One B-rep face of a CAD part: STEP entity #48906.
In plain terms, the planar face has unit normal (0, 0, 1).
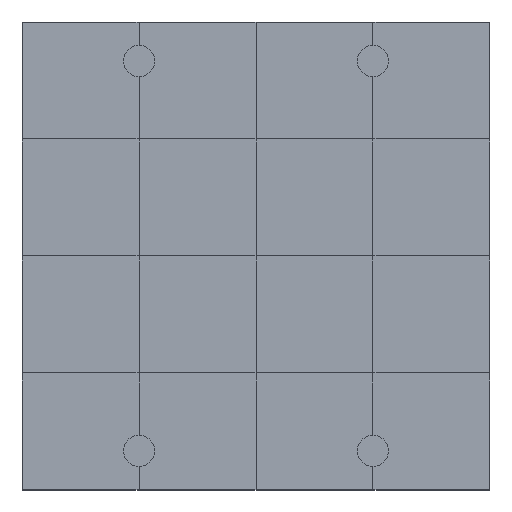
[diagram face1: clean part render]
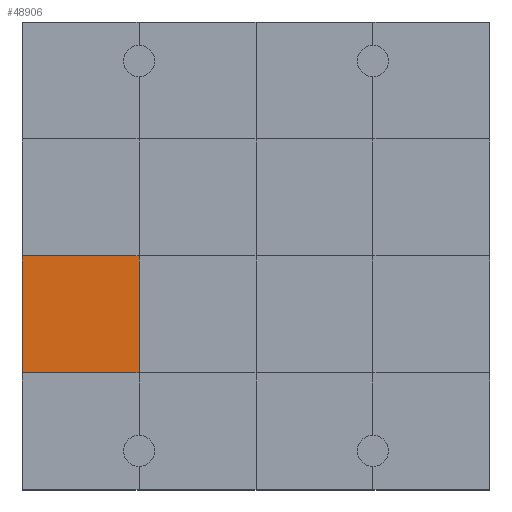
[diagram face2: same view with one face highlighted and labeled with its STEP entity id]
Its self-contained STEP definition (entity closure, numbers rounded to 3 decimals):
#48456 = VERTEX_POINT('',#48457);
#48457 = CARTESIAN_POINT('',(0.,3.,1.2));
#48471 = PLANE('',#48472);
#48472 = AXIS2_PLACEMENT_3D('',#48473,#48474,#48475);
#48473 = CARTESIAN_POINT('',(0.,3.,0.));
#48474 = DIRECTION('',(1.,0.,-0.));
#48475 = DIRECTION('',(0.,0.,1.));
#48497 = PLANE('',#48498);
#48498 = AXIS2_PLACEMENT_3D('',#48499,#48500,#48501);
#48499 = CARTESIAN_POINT('',(0.,0.,1.2));
#48500 = DIRECTION('',(0.,0.,1.));
#48501 = DIRECTION('',(1.,0.,-0.));
#48648 = VERTEX_POINT('',#48649);
#48649 = CARTESIAN_POINT('',(3.,3.,1.2));
#48670 = EDGE_CURVE('',#48456,#48648,#48671,.T.);
#48671 = SURFACE_CURVE('',#48672,(#48676,#48683),.PCURVE_S1.);
#48672 = LINE('',#48673,#48674);
#48673 = CARTESIAN_POINT('',(0.,3.,1.2));
#48674 = VECTOR('',#48675,1.);
#48675 = DIRECTION('',(1.,0.,-0.));
#48676 = PCURVE('',#48497,#48677);
#48677 = DEFINITIONAL_REPRESENTATION('',(#48678),#48682);
#48678 = LINE('',#48679,#48680);
#48679 = CARTESIAN_POINT('',(0.,3.));
#48680 = VECTOR('',#48681,1.);
#48681 = DIRECTION('',(1.,0.));
#48682 = ( GEOMETRIC_REPRESENTATION_CONTEXT(2) 
PARAMETRIC_REPRESENTATION_CONTEXT() REPRESENTATION_CONTEXT('2D SPACE',''
  ) );
#48683 = PCURVE('',#48684,#48689);
#48684 = PLANE('',#48685);
#48685 = AXIS2_PLACEMENT_3D('',#48686,#48687,#48688);
#48686 = CARTESIAN_POINT('',(0.,3.,1.2));
#48687 = DIRECTION('',(0.,0.,1.));
#48688 = DIRECTION('',(1.,0.,-0.));
#48689 = DEFINITIONAL_REPRESENTATION('',(#48690),#48694);
#48690 = LINE('',#48691,#48692);
#48691 = CARTESIAN_POINT('',(0.,0.));
#48692 = VECTOR('',#48693,1.);
#48693 = DIRECTION('',(1.,0.));
#48694 = ( GEOMETRIC_REPRESENTATION_CONTEXT(2) 
PARAMETRIC_REPRESENTATION_CONTEXT() REPRESENTATION_CONTEXT('2D SPACE',''
  ) );
#48729 = VERTEX_POINT('',#48730);
#48730 = CARTESIAN_POINT('',(0.,6.,1.2));
#48756 = EDGE_CURVE('',#48456,#48729,#48757,.T.);
#48757 = SURFACE_CURVE('',#48758,(#48762,#48769),.PCURVE_S1.);
#48758 = LINE('',#48759,#48760);
#48759 = CARTESIAN_POINT('',(0.,3.,1.2));
#48760 = VECTOR('',#48761,1.);
#48761 = DIRECTION('',(-0.,1.,0.));
#48762 = PCURVE('',#48471,#48763);
#48763 = DEFINITIONAL_REPRESENTATION('',(#48764),#48768);
#48764 = LINE('',#48765,#48766);
#48765 = CARTESIAN_POINT('',(1.2,0.));
#48766 = VECTOR('',#48767,1.);
#48767 = DIRECTION('',(0.,-1.));
#48768 = ( GEOMETRIC_REPRESENTATION_CONTEXT(2) 
PARAMETRIC_REPRESENTATION_CONTEXT() REPRESENTATION_CONTEXT('2D SPACE',''
  ) );
#48769 = PCURVE('',#48684,#48770);
#48770 = DEFINITIONAL_REPRESENTATION('',(#48771),#48775);
#48771 = LINE('',#48772,#48773);
#48772 = CARTESIAN_POINT('',(0.,0.));
#48773 = VECTOR('',#48774,1.);
#48774 = DIRECTION('',(0.,1.));
#48775 = ( GEOMETRIC_REPRESENTATION_CONTEXT(2) 
PARAMETRIC_REPRESENTATION_CONTEXT() REPRESENTATION_CONTEXT('2D SPACE',''
  ) );
#48906 = ADVANCED_FACE('',(#48907),#48684,.T.);
#48907 = FACE_BOUND('',#48908,.T.);
#48908 = EDGE_LOOP('',(#48909,#48910,#48911,#48939));
#48909 = ORIENTED_EDGE('',*,*,#48756,.F.);
#48910 = ORIENTED_EDGE('',*,*,#48670,.T.);
#48911 = ORIENTED_EDGE('',*,*,#48912,.T.);
#48912 = EDGE_CURVE('',#48648,#48913,#48915,.T.);
#48913 = VERTEX_POINT('',#48914);
#48914 = CARTESIAN_POINT('',(3.,6.,1.2));
#48915 = SURFACE_CURVE('',#48916,(#48920,#48927),.PCURVE_S1.);
#48916 = LINE('',#48917,#48918);
#48917 = CARTESIAN_POINT('',(3.,3.,1.2));
#48918 = VECTOR('',#48919,1.);
#48919 = DIRECTION('',(-0.,1.,0.));
#48920 = PCURVE('',#48684,#48921);
#48921 = DEFINITIONAL_REPRESENTATION('',(#48922),#48926);
#48922 = LINE('',#48923,#48924);
#48923 = CARTESIAN_POINT('',(3.,0.));
#48924 = VECTOR('',#48925,1.);
#48925 = DIRECTION('',(0.,1.));
#48926 = ( GEOMETRIC_REPRESENTATION_CONTEXT(2) 
PARAMETRIC_REPRESENTATION_CONTEXT() REPRESENTATION_CONTEXT('2D SPACE',''
  ) );
#48927 = PCURVE('',#48928,#48933);
#48928 = PLANE('',#48929);
#48929 = AXIS2_PLACEMENT_3D('',#48930,#48931,#48932);
#48930 = CARTESIAN_POINT('',(3.,3.,1.2));
#48931 = DIRECTION('',(0.,0.,1.));
#48932 = DIRECTION('',(1.,0.,-0.));
#48933 = DEFINITIONAL_REPRESENTATION('',(#48934),#48938);
#48934 = LINE('',#48935,#48936);
#48935 = CARTESIAN_POINT('',(0.,0.));
#48936 = VECTOR('',#48937,1.);
#48937 = DIRECTION('',(0.,1.));
#48938 = ( GEOMETRIC_REPRESENTATION_CONTEXT(2) 
PARAMETRIC_REPRESENTATION_CONTEXT() REPRESENTATION_CONTEXT('2D SPACE',''
  ) );
#48939 = ORIENTED_EDGE('',*,*,#48940,.F.);
#48940 = EDGE_CURVE('',#48729,#48913,#48941,.T.);
#48941 = SURFACE_CURVE('',#48942,(#48946,#48953),.PCURVE_S1.);
#48942 = LINE('',#48943,#48944);
#48943 = CARTESIAN_POINT('',(0.,6.,1.2));
#48944 = VECTOR('',#48945,1.);
#48945 = DIRECTION('',(1.,0.,-0.));
#48946 = PCURVE('',#48684,#48947);
#48947 = DEFINITIONAL_REPRESENTATION('',(#48948),#48952);
#48948 = LINE('',#48949,#48950);
#48949 = CARTESIAN_POINT('',(0.,3.));
#48950 = VECTOR('',#48951,1.);
#48951 = DIRECTION('',(1.,0.));
#48952 = ( GEOMETRIC_REPRESENTATION_CONTEXT(2) 
PARAMETRIC_REPRESENTATION_CONTEXT() REPRESENTATION_CONTEXT('2D SPACE',''
  ) );
#48953 = PCURVE('',#48954,#48959);
#48954 = PLANE('',#48955);
#48955 = AXIS2_PLACEMENT_3D('',#48956,#48957,#48958);
#48956 = CARTESIAN_POINT('',(0.,6.,1.2));
#48957 = DIRECTION('',(0.,0.,1.));
#48958 = DIRECTION('',(1.,0.,-0.));
#48959 = DEFINITIONAL_REPRESENTATION('',(#48960),#48964);
#48960 = LINE('',#48961,#48962);
#48961 = CARTESIAN_POINT('',(0.,0.));
#48962 = VECTOR('',#48963,1.);
#48963 = DIRECTION('',(1.,0.));
#48964 = ( GEOMETRIC_REPRESENTATION_CONTEXT(2) 
PARAMETRIC_REPRESENTATION_CONTEXT() REPRESENTATION_CONTEXT('2D SPACE',''
  ) );
